VERSION 5.7 ;
  NOWIREEXTENSIONATPIN ON ;
  DIVIDERCHAR "/" ;
  BUSBITCHARS "[]" ;
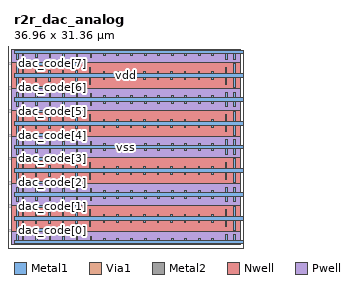
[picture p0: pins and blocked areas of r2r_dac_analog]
MACRO r2r_dac_analog
  CLASS BLOCK ;
  FOREIGN r2r_dac_analog ;
  ORIGIN -165.520 0.000 ;
  SIZE 36.960 BY 31.360 ;
  PIN dac_code[7]
    ANTENNAGATEAREA 11.020000 ;
    PORT
      LAYER Metal1 ;
        RECT 167.270 29.210 176.540 29.620 ;
    END
  END dac_code[7]
  PIN dac_code[6]
    ANTENNAGATEAREA 11.020000 ;
    PORT
      LAYER Metal1 ;
        RECT 167.270 25.260 176.540 25.670 ;
    END
  END dac_code[6]
  PIN dac_code[5]
    ANTENNAGATEAREA 11.020000 ;
    PORT
      LAYER Metal1 ;
        RECT 167.270 21.370 176.540 21.780 ;
    END
  END dac_code[5]
  PIN dac_code[4]
    ANTENNAGATEAREA 11.020000 ;
    PORT
      LAYER Metal1 ;
        RECT 167.270 17.420 176.540 17.830 ;
    END
  END dac_code[4]
  PIN dac_code[3]
    ANTENNAGATEAREA 11.020000 ;
    PORT
      LAYER Metal1 ;
        RECT 167.270 13.530 176.540 13.940 ;
    END
  END dac_code[3]
  PIN dac_code[2]
    ANTENNAGATEAREA 11.020000 ;
    PORT
      LAYER Metal1 ;
        RECT 167.270 9.580 176.540 9.990 ;
    END
  END dac_code[2]
  PIN dac_code[1]
    ANTENNAGATEAREA 11.020000 ;
    PORT
      LAYER Metal1 ;
        RECT 167.270 5.690 176.540 6.100 ;
    END
  END dac_code[1]
  PIN dac_code[0]
    ANTENNAGATEAREA 11.020000 ;
    PORT
      LAYER Metal1 ;
        RECT 167.270 1.740 176.540 2.150 ;
    END
  END dac_code[0]
  PIN vout
    DIRECTION INOUT ;
    USE SIGNAL ;
    PORT
      LAYER Metal1 ;
        RECT -0.520 130.010 -0.140 130.060 ;
        RECT -0.530 129.610 -0.130 130.010 ;
        RECT -0.520 128.660 -0.140 129.610 ;
        RECT -0.520 126.010 -0.140 126.060 ;
        RECT -0.530 125.610 -0.130 126.010 ;
        RECT 153.320 125.610 153.720 130.010 ;
        RECT -0.520 124.660 -0.140 125.610 ;
      LAYER Via1 ;
        RECT -0.460 129.680 -0.200 129.940 ;
        RECT 153.390 129.680 153.650 129.940 ;
        RECT -0.460 125.680 -0.200 125.940 ;
        RECT 153.390 125.680 153.650 125.940 ;
      LAYER Metal2 ;
        RECT -0.530 129.610 153.720 130.010 ;
        RECT -0.530 125.610 153.720 126.010 ;
    END
  END vout
  PIN vdd
    DIRECTION INOUT ;
    USE POWER ;
    PORT
      LAYER Nwell ;
        RECT 165.090 25.280 202.910 29.600 ;
        RECT 165.090 17.440 202.910 21.760 ;
        RECT 165.090 9.600 202.910 13.920 ;
        RECT 165.090 1.760 202.910 6.080 ;
      LAYER Metal1 ;
        RECT 165.910 27.740 166.250 29.430 ;
        RECT 166.885 27.740 167.115 28.830 ;
        RECT 169.025 27.740 169.255 28.360 ;
        RECT 171.265 27.740 171.495 28.360 ;
        RECT 173.505 27.740 173.735 28.360 ;
        RECT 175.745 27.740 175.975 28.360 ;
        RECT 177.985 27.740 178.215 28.830 ;
        RECT 180.225 27.740 180.455 28.130 ;
        RECT 182.465 27.740 182.695 28.130 ;
        RECT 184.705 27.740 184.935 28.130 ;
        RECT 186.945 27.740 187.175 28.130 ;
        RECT 189.185 27.740 189.415 28.130 ;
        RECT 191.425 27.740 191.655 28.130 ;
        RECT 193.665 27.740 193.895 28.130 ;
        RECT 195.905 27.740 196.135 28.130 ;
        RECT 198.145 27.740 198.375 28.130 ;
        RECT 200.385 27.740 200.615 28.830 ;
        RECT 201.750 27.740 202.090 29.430 ;
        RECT 165.520 27.140 204.280 27.740 ;
        RECT 165.910 25.450 166.250 27.140 ;
        RECT 166.885 26.050 167.115 27.140 ;
        RECT 169.025 26.520 169.255 27.140 ;
        RECT 171.265 26.520 171.495 27.140 ;
        RECT 173.505 26.520 173.735 27.140 ;
        RECT 175.745 26.520 175.975 27.140 ;
        RECT 177.985 26.050 178.215 27.140 ;
        RECT 180.225 26.750 180.455 27.140 ;
        RECT 182.465 26.750 182.695 27.140 ;
        RECT 184.705 26.750 184.935 27.140 ;
        RECT 186.945 26.750 187.175 27.140 ;
        RECT 189.185 26.750 189.415 27.140 ;
        RECT 191.425 26.750 191.655 27.140 ;
        RECT 193.665 26.750 193.895 27.140 ;
        RECT 195.905 26.750 196.135 27.140 ;
        RECT 198.145 26.750 198.375 27.140 ;
        RECT 200.385 26.050 200.615 27.140 ;
        RECT 201.750 25.450 202.090 27.140 ;
        RECT 165.910 19.900 166.250 21.590 ;
        RECT 166.885 19.900 167.115 20.990 ;
        RECT 169.025 19.900 169.255 20.520 ;
        RECT 171.265 19.900 171.495 20.520 ;
        RECT 173.505 19.900 173.735 20.520 ;
        RECT 175.745 19.900 175.975 20.520 ;
        RECT 177.985 19.900 178.215 20.990 ;
        RECT 180.225 19.900 180.455 20.290 ;
        RECT 182.465 19.900 182.695 20.290 ;
        RECT 184.705 19.900 184.935 20.290 ;
        RECT 186.945 19.900 187.175 20.290 ;
        RECT 189.185 19.900 189.415 20.290 ;
        RECT 191.425 19.900 191.655 20.290 ;
        RECT 193.665 19.900 193.895 20.290 ;
        RECT 195.905 19.900 196.135 20.290 ;
        RECT 198.145 19.900 198.375 20.290 ;
        RECT 200.385 19.900 200.615 20.990 ;
        RECT 201.750 19.900 202.090 21.590 ;
        RECT 165.520 19.300 204.280 19.900 ;
        RECT 165.910 17.610 166.250 19.300 ;
        RECT 166.885 18.210 167.115 19.300 ;
        RECT 169.025 18.680 169.255 19.300 ;
        RECT 171.265 18.680 171.495 19.300 ;
        RECT 173.505 18.680 173.735 19.300 ;
        RECT 175.745 18.680 175.975 19.300 ;
        RECT 177.985 18.210 178.215 19.300 ;
        RECT 180.225 18.910 180.455 19.300 ;
        RECT 182.465 18.910 182.695 19.300 ;
        RECT 184.705 18.910 184.935 19.300 ;
        RECT 186.945 18.910 187.175 19.300 ;
        RECT 189.185 18.910 189.415 19.300 ;
        RECT 191.425 18.910 191.655 19.300 ;
        RECT 193.665 18.910 193.895 19.300 ;
        RECT 195.905 18.910 196.135 19.300 ;
        RECT 198.145 18.910 198.375 19.300 ;
        RECT 200.385 18.210 200.615 19.300 ;
        RECT 201.750 17.610 202.090 19.300 ;
        RECT 165.910 12.060 166.250 13.750 ;
        RECT 166.885 12.060 167.115 13.150 ;
        RECT 169.025 12.060 169.255 12.680 ;
        RECT 171.265 12.060 171.495 12.680 ;
        RECT 173.505 12.060 173.735 12.680 ;
        RECT 175.745 12.060 175.975 12.680 ;
        RECT 177.985 12.060 178.215 13.150 ;
        RECT 180.225 12.060 180.455 12.450 ;
        RECT 182.465 12.060 182.695 12.450 ;
        RECT 184.705 12.060 184.935 12.450 ;
        RECT 186.945 12.060 187.175 12.450 ;
        RECT 189.185 12.060 189.415 12.450 ;
        RECT 191.425 12.060 191.655 12.450 ;
        RECT 193.665 12.060 193.895 12.450 ;
        RECT 195.905 12.060 196.135 12.450 ;
        RECT 198.145 12.060 198.375 12.450 ;
        RECT 200.385 12.060 200.615 13.150 ;
        RECT 201.750 12.060 202.090 13.750 ;
        RECT 165.520 11.460 204.280 12.060 ;
        RECT 165.910 9.770 166.250 11.460 ;
        RECT 166.885 10.370 167.115 11.460 ;
        RECT 169.025 10.840 169.255 11.460 ;
        RECT 171.265 10.840 171.495 11.460 ;
        RECT 173.505 10.840 173.735 11.460 ;
        RECT 175.745 10.840 175.975 11.460 ;
        RECT 177.985 10.370 178.215 11.460 ;
        RECT 180.225 11.070 180.455 11.460 ;
        RECT 182.465 11.070 182.695 11.460 ;
        RECT 184.705 11.070 184.935 11.460 ;
        RECT 186.945 11.070 187.175 11.460 ;
        RECT 189.185 11.070 189.415 11.460 ;
        RECT 191.425 11.070 191.655 11.460 ;
        RECT 193.665 11.070 193.895 11.460 ;
        RECT 195.905 11.070 196.135 11.460 ;
        RECT 198.145 11.070 198.375 11.460 ;
        RECT 200.385 10.370 200.615 11.460 ;
        RECT 201.750 9.770 202.090 11.460 ;
        RECT 165.910 4.220 166.250 5.910 ;
        RECT 166.885 4.220 167.115 5.310 ;
        RECT 169.025 4.220 169.255 4.840 ;
        RECT 171.265 4.220 171.495 4.840 ;
        RECT 173.505 4.220 173.735 4.840 ;
        RECT 175.745 4.220 175.975 4.840 ;
        RECT 177.985 4.220 178.215 5.310 ;
        RECT 180.225 4.220 180.455 4.610 ;
        RECT 182.465 4.220 182.695 4.610 ;
        RECT 184.705 4.220 184.935 4.610 ;
        RECT 186.945 4.220 187.175 4.610 ;
        RECT 189.185 4.220 189.415 4.610 ;
        RECT 191.425 4.220 191.655 4.610 ;
        RECT 193.665 4.220 193.895 4.610 ;
        RECT 195.905 4.220 196.135 4.610 ;
        RECT 198.145 4.220 198.375 4.610 ;
        RECT 200.385 4.220 200.615 5.310 ;
        RECT 201.750 4.220 202.090 5.910 ;
        RECT 165.520 3.620 204.280 4.220 ;
        RECT 165.910 1.930 166.250 3.620 ;
        RECT 166.885 2.530 167.115 3.620 ;
        RECT 169.025 3.000 169.255 3.620 ;
        RECT 171.265 3.000 171.495 3.620 ;
        RECT 173.505 3.000 173.735 3.620 ;
        RECT 175.745 3.000 175.975 3.620 ;
        RECT 177.985 2.530 178.215 3.620 ;
        RECT 180.225 3.230 180.455 3.620 ;
        RECT 182.465 3.230 182.695 3.620 ;
        RECT 184.705 3.230 184.935 3.620 ;
        RECT 186.945 3.230 187.175 3.620 ;
        RECT 189.185 3.230 189.415 3.620 ;
        RECT 191.425 3.230 191.655 3.620 ;
        RECT 193.665 3.230 193.895 3.620 ;
        RECT 195.905 3.230 196.135 3.620 ;
        RECT 198.145 3.230 198.375 3.620 ;
        RECT 200.385 2.530 200.615 3.620 ;
        RECT 201.750 1.930 202.090 3.620 ;
      LAYER Via1 ;
        RECT 203.850 27.310 204.110 27.570 ;
        RECT 203.850 19.470 204.110 19.730 ;
        RECT 203.850 11.630 204.110 11.890 ;
        RECT 203.850 3.790 204.110 4.050 ;
      LAYER Metal2 ;
        RECT 203.780 3.720 204.180 27.640 ;
    END
  END vdd
  PIN vss
    DIRECTION INOUT ;
    USE GROUND ;
    PORT
      LAYER Pwell ;
        RECT 165.090 29.600 202.910 31.790 ;
        RECT 165.090 21.760 202.910 25.280 ;
        RECT 165.090 13.920 202.910 17.440 ;
        RECT 165.090 6.080 202.910 9.600 ;
        RECT 165.090 -0.430 202.910 1.760 ;
      LAYER Metal1 ;
        RECT -1.890 -2.800 -1.510 136.360 ;
        RECT 150.140 37.110 150.520 38.060 ;
        RECT 150.130 36.710 150.530 37.110 ;
        RECT 150.140 36.660 150.520 36.710 ;
        RECT -1.900 -3.200 -1.500 -2.800 ;
        RECT 152.320 -3.200 152.720 37.110 ;
        RECT 165.520 31.060 205.780 31.660 ;
        RECT 165.910 30.175 166.250 31.060 ;
        RECT 166.885 30.200 167.115 31.060 ;
        RECT 169.125 30.400 169.355 31.060 ;
        RECT 171.365 30.400 171.595 31.060 ;
        RECT 173.605 30.400 173.835 31.060 ;
        RECT 175.845 30.400 176.075 31.060 ;
        RECT 178.085 30.400 178.315 31.060 ;
        RECT 180.270 30.725 180.610 31.060 ;
        RECT 182.510 30.725 182.850 31.060 ;
        RECT 184.750 30.725 185.090 31.060 ;
        RECT 186.990 30.725 187.330 31.060 ;
        RECT 189.230 30.725 189.570 31.060 ;
        RECT 191.470 30.725 191.810 31.060 ;
        RECT 193.710 30.725 194.050 31.060 ;
        RECT 195.950 30.725 196.290 31.060 ;
        RECT 198.190 30.725 198.530 31.060 ;
        RECT 200.485 30.200 200.715 31.060 ;
        RECT 201.750 30.175 202.090 31.060 ;
        RECT 165.910 23.820 166.250 24.705 ;
        RECT 166.885 23.820 167.115 24.680 ;
        RECT 169.125 23.820 169.355 24.480 ;
        RECT 171.365 23.820 171.595 24.480 ;
        RECT 173.605 23.820 173.835 24.480 ;
        RECT 175.845 23.820 176.075 24.480 ;
        RECT 178.085 23.820 178.315 24.480 ;
        RECT 180.270 23.820 180.610 24.155 ;
        RECT 182.510 23.820 182.850 24.155 ;
        RECT 184.750 23.820 185.090 24.155 ;
        RECT 186.990 23.820 187.330 24.155 ;
        RECT 189.230 23.820 189.570 24.155 ;
        RECT 191.470 23.820 191.810 24.155 ;
        RECT 193.710 23.820 194.050 24.155 ;
        RECT 195.950 23.820 196.290 24.155 ;
        RECT 198.190 23.820 198.530 24.155 ;
        RECT 200.485 23.820 200.715 24.680 ;
        RECT 201.750 23.820 202.090 24.705 ;
        RECT 165.520 23.220 205.780 23.820 ;
        RECT 165.910 22.335 166.250 23.220 ;
        RECT 166.885 22.360 167.115 23.220 ;
        RECT 169.125 22.560 169.355 23.220 ;
        RECT 171.365 22.560 171.595 23.220 ;
        RECT 173.605 22.560 173.835 23.220 ;
        RECT 175.845 22.560 176.075 23.220 ;
        RECT 178.085 22.560 178.315 23.220 ;
        RECT 180.270 22.885 180.610 23.220 ;
        RECT 182.510 22.885 182.850 23.220 ;
        RECT 184.750 22.885 185.090 23.220 ;
        RECT 186.990 22.885 187.330 23.220 ;
        RECT 189.230 22.885 189.570 23.220 ;
        RECT 191.470 22.885 191.810 23.220 ;
        RECT 193.710 22.885 194.050 23.220 ;
        RECT 195.950 22.885 196.290 23.220 ;
        RECT 198.190 22.885 198.530 23.220 ;
        RECT 200.485 22.360 200.715 23.220 ;
        RECT 201.750 22.335 202.090 23.220 ;
        RECT 165.910 15.980 166.250 16.865 ;
        RECT 166.885 15.980 167.115 16.840 ;
        RECT 169.125 15.980 169.355 16.640 ;
        RECT 171.365 15.980 171.595 16.640 ;
        RECT 173.605 15.980 173.835 16.640 ;
        RECT 175.845 15.980 176.075 16.640 ;
        RECT 178.085 15.980 178.315 16.640 ;
        RECT 180.270 15.980 180.610 16.315 ;
        RECT 182.510 15.980 182.850 16.315 ;
        RECT 184.750 15.980 185.090 16.315 ;
        RECT 186.990 15.980 187.330 16.315 ;
        RECT 189.230 15.980 189.570 16.315 ;
        RECT 191.470 15.980 191.810 16.315 ;
        RECT 193.710 15.980 194.050 16.315 ;
        RECT 195.950 15.980 196.290 16.315 ;
        RECT 198.190 15.980 198.530 16.315 ;
        RECT 200.485 15.980 200.715 16.840 ;
        RECT 201.750 15.980 202.090 16.865 ;
        RECT 165.520 15.380 205.780 15.980 ;
        RECT 165.910 14.495 166.250 15.380 ;
        RECT 166.885 14.520 167.115 15.380 ;
        RECT 169.125 14.720 169.355 15.380 ;
        RECT 171.365 14.720 171.595 15.380 ;
        RECT 173.605 14.720 173.835 15.380 ;
        RECT 175.845 14.720 176.075 15.380 ;
        RECT 178.085 14.720 178.315 15.380 ;
        RECT 180.270 15.045 180.610 15.380 ;
        RECT 182.510 15.045 182.850 15.380 ;
        RECT 184.750 15.045 185.090 15.380 ;
        RECT 186.990 15.045 187.330 15.380 ;
        RECT 189.230 15.045 189.570 15.380 ;
        RECT 191.470 15.045 191.810 15.380 ;
        RECT 193.710 15.045 194.050 15.380 ;
        RECT 195.950 15.045 196.290 15.380 ;
        RECT 198.190 15.045 198.530 15.380 ;
        RECT 200.485 14.520 200.715 15.380 ;
        RECT 201.750 14.495 202.090 15.380 ;
        RECT 165.910 8.140 166.250 9.025 ;
        RECT 166.885 8.140 167.115 9.000 ;
        RECT 169.125 8.140 169.355 8.800 ;
        RECT 171.365 8.140 171.595 8.800 ;
        RECT 173.605 8.140 173.835 8.800 ;
        RECT 175.845 8.140 176.075 8.800 ;
        RECT 178.085 8.140 178.315 8.800 ;
        RECT 180.270 8.140 180.610 8.475 ;
        RECT 182.510 8.140 182.850 8.475 ;
        RECT 184.750 8.140 185.090 8.475 ;
        RECT 186.990 8.140 187.330 8.475 ;
        RECT 189.230 8.140 189.570 8.475 ;
        RECT 191.470 8.140 191.810 8.475 ;
        RECT 193.710 8.140 194.050 8.475 ;
        RECT 195.950 8.140 196.290 8.475 ;
        RECT 198.190 8.140 198.530 8.475 ;
        RECT 200.485 8.140 200.715 9.000 ;
        RECT 201.750 8.140 202.090 9.025 ;
        RECT 165.520 7.540 205.780 8.140 ;
        RECT 165.910 6.655 166.250 7.540 ;
        RECT 166.885 6.680 167.115 7.540 ;
        RECT 169.125 6.880 169.355 7.540 ;
        RECT 171.365 6.880 171.595 7.540 ;
        RECT 173.605 6.880 173.835 7.540 ;
        RECT 175.845 6.880 176.075 7.540 ;
        RECT 178.085 6.880 178.315 7.540 ;
        RECT 180.270 7.205 180.610 7.540 ;
        RECT 182.510 7.205 182.850 7.540 ;
        RECT 184.750 7.205 185.090 7.540 ;
        RECT 186.990 7.205 187.330 7.540 ;
        RECT 189.230 7.205 189.570 7.540 ;
        RECT 191.470 7.205 191.810 7.540 ;
        RECT 193.710 7.205 194.050 7.540 ;
        RECT 195.950 7.205 196.290 7.540 ;
        RECT 198.190 7.205 198.530 7.540 ;
        RECT 200.485 6.680 200.715 7.540 ;
        RECT 201.750 6.655 202.090 7.540 ;
        RECT 165.910 0.300 166.250 1.185 ;
        RECT 166.885 0.300 167.115 1.160 ;
        RECT 169.125 0.300 169.355 0.960 ;
        RECT 171.365 0.300 171.595 0.960 ;
        RECT 173.605 0.300 173.835 0.960 ;
        RECT 175.845 0.300 176.075 0.960 ;
        RECT 178.085 0.300 178.315 0.960 ;
        RECT 180.270 0.300 180.610 0.635 ;
        RECT 182.510 0.300 182.850 0.635 ;
        RECT 184.750 0.300 185.090 0.635 ;
        RECT 186.990 0.300 187.330 0.635 ;
        RECT 189.230 0.300 189.570 0.635 ;
        RECT 191.470 0.300 191.810 0.635 ;
        RECT 193.710 0.300 194.050 0.635 ;
        RECT 195.950 0.300 196.290 0.635 ;
        RECT 198.190 0.300 198.530 0.635 ;
        RECT 200.485 0.300 200.715 1.160 ;
        RECT 201.750 0.300 202.090 1.185 ;
        RECT 165.520 -0.300 205.780 0.300 ;
        RECT 205.280 -3.200 205.680 -2.800 ;
      LAYER Via1 ;
        RECT 150.200 36.780 150.460 37.040 ;
        RECT 152.390 36.780 152.650 37.040 ;
        RECT -1.830 -3.130 -1.570 -2.870 ;
        RECT 205.350 31.230 205.610 31.490 ;
        RECT 205.350 23.390 205.610 23.650 ;
        RECT 205.350 15.550 205.610 15.810 ;
        RECT 205.350 7.710 205.610 7.970 ;
        RECT 205.350 -0.130 205.610 0.130 ;
        RECT 152.390 -3.130 152.650 -2.870 ;
        RECT 205.350 -3.130 205.610 -2.870 ;
      LAYER Metal2 ;
        RECT 150.130 36.710 152.720 37.110 ;
        RECT 205.280 -2.800 205.680 31.560 ;
        RECT -1.900 -3.200 205.680 -2.800 ;
    END
  END vss
  OBS
      LAYER Metal1 ;
        RECT -0.520 134.010 -0.140 134.060 ;
        RECT -0.530 133.610 -0.130 134.010 ;
        RECT -0.520 132.660 -0.140 133.610 ;
        RECT 150.140 133.110 150.520 134.060 ;
        RECT 150.130 132.710 150.530 133.110 ;
        RECT 150.140 132.660 150.520 132.710 ;
        RECT 148.500 129.110 148.880 130.060 ;
        RECT 148.490 128.710 148.890 129.110 ;
        RECT 152.320 128.710 152.720 133.110 ;
        RECT 148.500 128.660 148.880 128.710 ;
        RECT 150.140 125.110 150.520 126.060 ;
        RECT 150.130 124.710 150.530 125.110 ;
        RECT 150.140 124.660 150.520 124.710 ;
        RECT -0.520 122.010 -0.140 122.060 ;
        RECT -0.530 121.610 -0.130 122.010 ;
        RECT -0.520 120.660 -0.140 121.610 ;
        RECT 150.140 121.110 150.520 122.060 ;
        RECT 150.130 120.710 150.530 121.110 ;
        RECT 150.140 120.660 150.520 120.710 ;
        RECT -0.520 118.010 -0.140 118.060 ;
        RECT -0.530 117.610 -0.130 118.010 ;
        RECT -0.520 116.660 -0.140 117.610 ;
        RECT 148.500 117.110 148.880 118.060 ;
        RECT 148.490 116.710 148.890 117.110 ;
        RECT 148.500 116.660 148.880 116.710 ;
        RECT -0.520 114.010 -0.140 114.060 ;
        RECT -0.530 113.610 -0.130 114.010 ;
        RECT -0.520 112.660 -0.140 113.610 ;
        RECT 150.140 113.110 150.520 114.060 ;
        RECT 152.320 113.610 152.720 125.110 ;
        RECT 153.320 116.710 153.720 121.110 ;
        RECT 150.130 112.710 150.530 113.110 ;
        RECT 150.140 112.660 150.520 112.710 ;
        RECT -0.520 110.010 -0.140 110.060 ;
        RECT -0.530 109.610 -0.130 110.010 ;
        RECT -0.520 108.660 -0.140 109.610 ;
        RECT 150.140 109.110 150.520 110.060 ;
        RECT 150.130 108.710 150.530 109.110 ;
        RECT 150.140 108.660 150.520 108.710 ;
        RECT -0.520 106.010 -0.140 106.060 ;
        RECT -0.530 105.610 -0.130 106.010 ;
        RECT -0.520 104.660 -0.140 105.610 ;
        RECT 148.500 105.110 148.880 106.060 ;
        RECT 148.490 104.710 148.890 105.110 ;
        RECT 152.320 104.710 152.720 109.110 ;
        RECT 148.500 104.660 148.880 104.710 ;
        RECT -0.520 102.010 -0.140 102.060 ;
        RECT -0.530 101.610 -0.130 102.010 ;
        RECT -0.520 100.660 -0.140 101.610 ;
        RECT 150.140 101.110 150.520 102.060 ;
        RECT 153.320 101.610 153.720 113.110 ;
        RECT 150.130 100.710 150.530 101.110 ;
        RECT 150.140 100.660 150.520 100.710 ;
        RECT -0.520 98.010 -0.140 98.060 ;
        RECT -0.530 97.610 -0.130 98.010 ;
        RECT -0.520 96.660 -0.140 97.610 ;
        RECT 150.140 97.110 150.520 98.060 ;
        RECT 150.130 96.710 150.530 97.110 ;
        RECT 150.140 96.660 150.520 96.710 ;
        RECT -0.520 94.010 -0.140 94.060 ;
        RECT -0.530 93.610 -0.130 94.010 ;
        RECT -0.520 92.660 -0.140 93.610 ;
        RECT 148.500 93.110 148.880 94.060 ;
        RECT 148.490 92.710 148.890 93.110 ;
        RECT 148.500 92.660 148.880 92.710 ;
        RECT -0.520 90.010 -0.140 90.060 ;
        RECT -0.530 89.610 -0.130 90.010 ;
        RECT -0.520 88.660 -0.140 89.610 ;
        RECT 150.140 89.110 150.520 90.060 ;
        RECT 152.320 89.610 152.720 101.110 ;
        RECT 153.320 92.710 153.720 97.110 ;
        RECT 150.130 88.710 150.530 89.110 ;
        RECT 150.140 88.660 150.520 88.710 ;
        RECT -0.520 86.010 -0.140 86.060 ;
        RECT -0.530 85.610 -0.130 86.010 ;
        RECT -0.520 84.660 -0.140 85.610 ;
        RECT 150.140 85.110 150.520 86.060 ;
        RECT 150.130 84.710 150.530 85.110 ;
        RECT 150.140 84.660 150.520 84.710 ;
        RECT -0.520 82.010 -0.140 82.060 ;
        RECT -0.530 81.610 -0.130 82.010 ;
        RECT -0.520 80.660 -0.140 81.610 ;
        RECT 148.500 81.110 148.880 82.060 ;
        RECT 148.490 80.710 148.890 81.110 ;
        RECT 152.320 80.710 152.720 85.110 ;
        RECT 148.500 80.660 148.880 80.710 ;
        RECT -0.520 78.010 -0.140 78.060 ;
        RECT -0.530 77.610 -0.130 78.010 ;
        RECT -0.520 76.660 -0.140 77.610 ;
        RECT 150.140 77.110 150.520 78.060 ;
        RECT 153.320 77.610 153.720 89.110 ;
        RECT 150.130 76.710 150.530 77.110 ;
        RECT 150.140 76.660 150.520 76.710 ;
        RECT -0.520 74.010 -0.140 74.060 ;
        RECT -0.530 73.610 -0.130 74.010 ;
        RECT -0.520 72.660 -0.140 73.610 ;
        RECT 150.140 73.110 150.520 74.060 ;
        RECT 150.130 72.710 150.530 73.110 ;
        RECT 150.140 72.660 150.520 72.710 ;
        RECT -0.520 70.010 -0.140 70.060 ;
        RECT -0.530 69.610 -0.130 70.010 ;
        RECT -0.520 68.660 -0.140 69.610 ;
        RECT 148.500 69.110 148.880 70.060 ;
        RECT 148.490 68.710 148.890 69.110 ;
        RECT 148.500 68.660 148.880 68.710 ;
        RECT -0.520 66.010 -0.140 66.060 ;
        RECT -0.530 65.610 -0.130 66.010 ;
        RECT -0.520 64.660 -0.140 65.610 ;
        RECT 150.140 65.110 150.520 66.060 ;
        RECT 152.320 65.610 152.720 77.110 ;
        RECT 153.320 68.710 153.720 73.110 ;
        RECT 150.130 64.710 150.530 65.110 ;
        RECT 150.140 64.660 150.520 64.710 ;
        RECT -0.520 62.010 -0.140 62.060 ;
        RECT -0.530 61.610 -0.130 62.010 ;
        RECT -0.520 60.660 -0.140 61.610 ;
        RECT 150.140 61.110 150.520 62.060 ;
        RECT 150.130 60.710 150.530 61.110 ;
        RECT 150.140 60.660 150.520 60.710 ;
        RECT -0.520 58.010 -0.140 58.060 ;
        RECT -0.530 57.610 -0.130 58.010 ;
        RECT -0.520 56.660 -0.140 57.610 ;
        RECT 148.500 57.110 148.880 58.060 ;
        RECT 148.490 56.710 148.890 57.110 ;
        RECT 152.320 56.710 152.720 61.110 ;
        RECT 148.500 56.660 148.880 56.710 ;
        RECT -0.520 54.010 -0.140 54.060 ;
        RECT -0.530 53.610 -0.130 54.010 ;
        RECT -0.520 52.660 -0.140 53.610 ;
        RECT 150.140 53.110 150.520 54.060 ;
        RECT 153.320 53.610 153.720 65.110 ;
        RECT 150.130 52.710 150.530 53.110 ;
        RECT 150.140 52.660 150.520 52.710 ;
        RECT -0.520 50.010 -0.140 50.060 ;
        RECT -0.530 49.610 -0.130 50.010 ;
        RECT -0.520 48.660 -0.140 49.610 ;
        RECT 150.140 49.110 150.520 50.060 ;
        RECT 150.130 48.710 150.530 49.110 ;
        RECT 150.140 48.660 150.520 48.710 ;
        RECT -0.520 46.010 -0.140 46.060 ;
        RECT -0.530 45.610 -0.130 46.010 ;
        RECT -0.520 44.660 -0.140 45.610 ;
        RECT 148.500 45.110 148.880 46.060 ;
        RECT 148.490 44.710 148.890 45.110 ;
        RECT 148.500 44.660 148.880 44.710 ;
        RECT -0.520 42.010 -0.140 42.060 ;
        RECT -0.530 41.610 -0.130 42.010 ;
        RECT -0.520 40.660 -0.140 41.610 ;
        RECT 150.140 41.110 150.520 42.060 ;
        RECT 152.320 41.610 152.720 53.110 ;
        RECT 150.130 40.710 150.530 41.110 ;
        RECT 150.140 40.660 150.520 40.710 ;
        RECT -0.520 38.010 -0.140 38.060 ;
        RECT -0.530 37.610 -0.130 38.010 ;
        RECT -0.520 36.660 -0.140 37.610 ;
        RECT 153.320 1.690 153.720 50.010 ;
        RECT 154.320 5.750 154.720 62.010 ;
        RECT 155.320 9.530 155.720 74.010 ;
        RECT 156.320 13.590 156.720 86.010 ;
        RECT 157.320 17.370 157.720 98.010 ;
        RECT 158.320 21.430 158.720 110.010 ;
        RECT 159.320 25.210 159.720 122.010 ;
        RECT 160.320 29.270 160.720 134.010 ;
        RECT 161.320 44.710 161.720 49.110 ;
        RECT 161.320 37.610 161.720 41.110 ;
        RECT 168.005 30.170 168.235 30.685 ;
        RECT 170.245 30.170 170.475 30.685 ;
        RECT 172.485 30.170 172.715 30.685 ;
        RECT 174.725 30.170 174.955 30.685 ;
        RECT 176.965 30.170 177.320 30.685 ;
        RECT 168.005 29.940 177.320 30.170 ;
        RECT 176.865 29.620 177.320 29.940 ;
        RECT 179.205 30.495 179.465 30.685 ;
        RECT 181.445 30.495 181.675 30.685 ;
        RECT 183.685 30.495 183.915 30.685 ;
        RECT 185.925 30.495 186.155 30.685 ;
        RECT 188.165 30.495 188.395 30.685 ;
        RECT 190.405 30.495 190.635 30.685 ;
        RECT 192.645 30.495 192.875 30.685 ;
        RECT 194.885 30.495 195.115 30.685 ;
        RECT 197.125 30.495 197.355 30.685 ;
        RECT 199.365 30.495 199.595 30.685 ;
        RECT 179.205 29.850 199.595 30.495 ;
        RECT 176.865 29.390 188.210 29.620 ;
        RECT 176.865 28.830 177.320 29.390 ;
        RECT 188.870 29.090 189.770 29.850 ;
        RECT 190.320 29.390 200.240 29.620 ;
        RECT 168.005 28.600 177.320 28.830 ;
        RECT 168.005 27.980 168.235 28.600 ;
        RECT 170.145 27.980 170.375 28.600 ;
        RECT 172.385 27.980 172.615 28.600 ;
        RECT 174.625 27.980 174.855 28.600 ;
        RECT 176.865 27.980 177.320 28.600 ;
        RECT 179.205 28.360 199.495 29.090 ;
        RECT 179.205 27.980 179.435 28.360 ;
        RECT 181.345 27.980 181.575 28.360 ;
        RECT 183.585 27.980 183.815 28.360 ;
        RECT 185.825 27.980 186.055 28.360 ;
        RECT 188.065 27.980 188.295 28.360 ;
        RECT 190.305 27.980 190.535 28.360 ;
        RECT 192.545 27.980 192.775 28.360 ;
        RECT 194.785 27.980 195.015 28.360 ;
        RECT 197.025 27.980 197.255 28.360 ;
        RECT 199.265 27.980 199.495 28.360 ;
        RECT 168.005 26.280 168.235 26.900 ;
        RECT 170.145 26.280 170.375 26.900 ;
        RECT 172.385 26.280 172.615 26.900 ;
        RECT 174.625 26.280 174.855 26.900 ;
        RECT 176.865 26.280 177.320 26.900 ;
        RECT 168.005 26.050 177.320 26.280 ;
        RECT 176.865 25.490 177.320 26.050 ;
        RECT 179.205 26.520 179.435 26.900 ;
        RECT 181.345 26.520 181.575 26.900 ;
        RECT 183.585 26.520 183.815 26.900 ;
        RECT 185.825 26.520 186.055 26.900 ;
        RECT 188.065 26.520 188.295 26.900 ;
        RECT 190.305 26.520 190.535 26.900 ;
        RECT 192.545 26.520 192.775 26.900 ;
        RECT 194.785 26.520 195.015 26.900 ;
        RECT 197.025 26.520 197.255 26.900 ;
        RECT 199.265 26.520 199.495 26.900 ;
        RECT 179.205 25.790 199.495 26.520 ;
        RECT 176.865 25.260 188.210 25.490 ;
        RECT 176.865 24.940 177.320 25.260 ;
        RECT 188.870 25.030 189.770 25.790 ;
        RECT 190.320 25.260 200.240 25.490 ;
        RECT 168.005 24.710 177.320 24.940 ;
        RECT 168.005 24.195 168.235 24.710 ;
        RECT 170.245 24.195 170.475 24.710 ;
        RECT 172.485 24.195 172.715 24.710 ;
        RECT 174.725 24.195 174.955 24.710 ;
        RECT 176.965 24.195 177.320 24.710 ;
        RECT 179.205 24.385 199.595 25.030 ;
        RECT 179.205 24.195 179.465 24.385 ;
        RECT 181.445 24.195 181.675 24.385 ;
        RECT 183.685 24.195 183.915 24.385 ;
        RECT 185.925 24.195 186.155 24.385 ;
        RECT 188.165 24.195 188.395 24.385 ;
        RECT 190.405 24.195 190.635 24.385 ;
        RECT 192.645 24.195 192.875 24.385 ;
        RECT 194.885 24.195 195.115 24.385 ;
        RECT 197.125 24.195 197.355 24.385 ;
        RECT 199.365 24.195 199.595 24.385 ;
        RECT 168.005 22.330 168.235 22.845 ;
        RECT 170.245 22.330 170.475 22.845 ;
        RECT 172.485 22.330 172.715 22.845 ;
        RECT 174.725 22.330 174.955 22.845 ;
        RECT 176.965 22.330 177.320 22.845 ;
        RECT 168.005 22.100 177.320 22.330 ;
        RECT 176.865 21.780 177.320 22.100 ;
        RECT 179.205 22.655 179.465 22.845 ;
        RECT 181.445 22.655 181.675 22.845 ;
        RECT 183.685 22.655 183.915 22.845 ;
        RECT 185.925 22.655 186.155 22.845 ;
        RECT 188.165 22.655 188.395 22.845 ;
        RECT 190.405 22.655 190.635 22.845 ;
        RECT 192.645 22.655 192.875 22.845 ;
        RECT 194.885 22.655 195.115 22.845 ;
        RECT 197.125 22.655 197.355 22.845 ;
        RECT 199.365 22.655 199.595 22.845 ;
        RECT 179.205 22.010 199.595 22.655 ;
        RECT 176.865 21.550 188.210 21.780 ;
        RECT 176.865 20.990 177.320 21.550 ;
        RECT 188.870 21.250 189.770 22.010 ;
        RECT 190.320 21.550 200.240 21.780 ;
        RECT 168.005 20.760 177.320 20.990 ;
        RECT 168.005 20.140 168.235 20.760 ;
        RECT 170.145 20.140 170.375 20.760 ;
        RECT 172.385 20.140 172.615 20.760 ;
        RECT 174.625 20.140 174.855 20.760 ;
        RECT 176.865 20.140 177.320 20.760 ;
        RECT 179.205 20.520 199.495 21.250 ;
        RECT 179.205 20.140 179.435 20.520 ;
        RECT 181.345 20.140 181.575 20.520 ;
        RECT 183.585 20.140 183.815 20.520 ;
        RECT 185.825 20.140 186.055 20.520 ;
        RECT 188.065 20.140 188.295 20.520 ;
        RECT 190.305 20.140 190.535 20.520 ;
        RECT 192.545 20.140 192.775 20.520 ;
        RECT 194.785 20.140 195.015 20.520 ;
        RECT 197.025 20.140 197.255 20.520 ;
        RECT 199.265 20.140 199.495 20.520 ;
        RECT 168.005 18.440 168.235 19.060 ;
        RECT 170.145 18.440 170.375 19.060 ;
        RECT 172.385 18.440 172.615 19.060 ;
        RECT 174.625 18.440 174.855 19.060 ;
        RECT 176.865 18.440 177.320 19.060 ;
        RECT 168.005 18.210 177.320 18.440 ;
        RECT 176.865 17.650 177.320 18.210 ;
        RECT 179.205 18.680 179.435 19.060 ;
        RECT 181.345 18.680 181.575 19.060 ;
        RECT 183.585 18.680 183.815 19.060 ;
        RECT 185.825 18.680 186.055 19.060 ;
        RECT 188.065 18.680 188.295 19.060 ;
        RECT 190.305 18.680 190.535 19.060 ;
        RECT 192.545 18.680 192.775 19.060 ;
        RECT 194.785 18.680 195.015 19.060 ;
        RECT 197.025 18.680 197.255 19.060 ;
        RECT 199.265 18.680 199.495 19.060 ;
        RECT 179.205 17.950 199.495 18.680 ;
        RECT 176.865 17.420 188.210 17.650 ;
        RECT 176.865 17.100 177.320 17.420 ;
        RECT 188.870 17.190 189.770 17.950 ;
        RECT 190.320 17.420 200.240 17.650 ;
        RECT 168.005 16.870 177.320 17.100 ;
        RECT 168.005 16.355 168.235 16.870 ;
        RECT 170.245 16.355 170.475 16.870 ;
        RECT 172.485 16.355 172.715 16.870 ;
        RECT 174.725 16.355 174.955 16.870 ;
        RECT 176.965 16.355 177.320 16.870 ;
        RECT 179.205 16.545 199.595 17.190 ;
        RECT 179.205 16.355 179.465 16.545 ;
        RECT 181.445 16.355 181.675 16.545 ;
        RECT 183.685 16.355 183.915 16.545 ;
        RECT 185.925 16.355 186.155 16.545 ;
        RECT 188.165 16.355 188.395 16.545 ;
        RECT 190.405 16.355 190.635 16.545 ;
        RECT 192.645 16.355 192.875 16.545 ;
        RECT 194.885 16.355 195.115 16.545 ;
        RECT 197.125 16.355 197.355 16.545 ;
        RECT 199.365 16.355 199.595 16.545 ;
        RECT 168.005 14.490 168.235 15.005 ;
        RECT 170.245 14.490 170.475 15.005 ;
        RECT 172.485 14.490 172.715 15.005 ;
        RECT 174.725 14.490 174.955 15.005 ;
        RECT 176.965 14.490 177.320 15.005 ;
        RECT 168.005 14.260 177.320 14.490 ;
        RECT 176.865 13.940 177.320 14.260 ;
        RECT 179.205 14.815 179.465 15.005 ;
        RECT 181.445 14.815 181.675 15.005 ;
        RECT 183.685 14.815 183.915 15.005 ;
        RECT 185.925 14.815 186.155 15.005 ;
        RECT 188.165 14.815 188.395 15.005 ;
        RECT 190.405 14.815 190.635 15.005 ;
        RECT 192.645 14.815 192.875 15.005 ;
        RECT 194.885 14.815 195.115 15.005 ;
        RECT 197.125 14.815 197.355 15.005 ;
        RECT 199.365 14.815 199.595 15.005 ;
        RECT 179.205 14.170 199.595 14.815 ;
        RECT 176.865 13.710 188.210 13.940 ;
        RECT 176.865 13.150 177.320 13.710 ;
        RECT 188.870 13.410 189.770 14.170 ;
        RECT 190.320 13.710 200.240 13.940 ;
        RECT 168.005 12.920 177.320 13.150 ;
        RECT 168.005 12.300 168.235 12.920 ;
        RECT 170.145 12.300 170.375 12.920 ;
        RECT 172.385 12.300 172.615 12.920 ;
        RECT 174.625 12.300 174.855 12.920 ;
        RECT 176.865 12.300 177.320 12.920 ;
        RECT 179.205 12.680 199.495 13.410 ;
        RECT 179.205 12.300 179.435 12.680 ;
        RECT 181.345 12.300 181.575 12.680 ;
        RECT 183.585 12.300 183.815 12.680 ;
        RECT 185.825 12.300 186.055 12.680 ;
        RECT 188.065 12.300 188.295 12.680 ;
        RECT 190.305 12.300 190.535 12.680 ;
        RECT 192.545 12.300 192.775 12.680 ;
        RECT 194.785 12.300 195.015 12.680 ;
        RECT 197.025 12.300 197.255 12.680 ;
        RECT 199.265 12.300 199.495 12.680 ;
        RECT 168.005 10.600 168.235 11.220 ;
        RECT 170.145 10.600 170.375 11.220 ;
        RECT 172.385 10.600 172.615 11.220 ;
        RECT 174.625 10.600 174.855 11.220 ;
        RECT 176.865 10.600 177.320 11.220 ;
        RECT 168.005 10.370 177.320 10.600 ;
        RECT 176.865 9.810 177.320 10.370 ;
        RECT 179.205 10.840 179.435 11.220 ;
        RECT 181.345 10.840 181.575 11.220 ;
        RECT 183.585 10.840 183.815 11.220 ;
        RECT 185.825 10.840 186.055 11.220 ;
        RECT 188.065 10.840 188.295 11.220 ;
        RECT 190.305 10.840 190.535 11.220 ;
        RECT 192.545 10.840 192.775 11.220 ;
        RECT 194.785 10.840 195.015 11.220 ;
        RECT 197.025 10.840 197.255 11.220 ;
        RECT 199.265 10.840 199.495 11.220 ;
        RECT 179.205 10.110 199.495 10.840 ;
        RECT 176.865 9.580 188.210 9.810 ;
        RECT 176.865 9.260 177.320 9.580 ;
        RECT 188.870 9.350 189.770 10.110 ;
        RECT 190.320 9.580 200.240 9.810 ;
        RECT 168.005 9.030 177.320 9.260 ;
        RECT 168.005 8.515 168.235 9.030 ;
        RECT 170.245 8.515 170.475 9.030 ;
        RECT 172.485 8.515 172.715 9.030 ;
        RECT 174.725 8.515 174.955 9.030 ;
        RECT 176.965 8.515 177.320 9.030 ;
        RECT 179.205 8.705 199.595 9.350 ;
        RECT 179.205 8.515 179.465 8.705 ;
        RECT 181.445 8.515 181.675 8.705 ;
        RECT 183.685 8.515 183.915 8.705 ;
        RECT 185.925 8.515 186.155 8.705 ;
        RECT 188.165 8.515 188.395 8.705 ;
        RECT 190.405 8.515 190.635 8.705 ;
        RECT 192.645 8.515 192.875 8.705 ;
        RECT 194.885 8.515 195.115 8.705 ;
        RECT 197.125 8.515 197.355 8.705 ;
        RECT 199.365 8.515 199.595 8.705 ;
        RECT 168.005 6.650 168.235 7.165 ;
        RECT 170.245 6.650 170.475 7.165 ;
        RECT 172.485 6.650 172.715 7.165 ;
        RECT 174.725 6.650 174.955 7.165 ;
        RECT 176.965 6.650 177.320 7.165 ;
        RECT 168.005 6.420 177.320 6.650 ;
        RECT 176.865 6.100 177.320 6.420 ;
        RECT 179.205 6.975 179.465 7.165 ;
        RECT 181.445 6.975 181.675 7.165 ;
        RECT 183.685 6.975 183.915 7.165 ;
        RECT 185.925 6.975 186.155 7.165 ;
        RECT 188.165 6.975 188.395 7.165 ;
        RECT 190.405 6.975 190.635 7.165 ;
        RECT 192.645 6.975 192.875 7.165 ;
        RECT 194.885 6.975 195.115 7.165 ;
        RECT 197.125 6.975 197.355 7.165 ;
        RECT 199.365 6.975 199.595 7.165 ;
        RECT 179.205 6.330 199.595 6.975 ;
        RECT 176.865 5.870 188.210 6.100 ;
        RECT 176.865 5.310 177.320 5.870 ;
        RECT 188.870 5.570 189.770 6.330 ;
        RECT 190.320 5.870 200.240 6.100 ;
        RECT 168.005 5.080 177.320 5.310 ;
        RECT 168.005 4.460 168.235 5.080 ;
        RECT 170.145 4.460 170.375 5.080 ;
        RECT 172.385 4.460 172.615 5.080 ;
        RECT 174.625 4.460 174.855 5.080 ;
        RECT 176.865 4.460 177.320 5.080 ;
        RECT 179.205 4.840 199.495 5.570 ;
        RECT 179.205 4.460 179.435 4.840 ;
        RECT 181.345 4.460 181.575 4.840 ;
        RECT 183.585 4.460 183.815 4.840 ;
        RECT 185.825 4.460 186.055 4.840 ;
        RECT 188.065 4.460 188.295 4.840 ;
        RECT 190.305 4.460 190.535 4.840 ;
        RECT 192.545 4.460 192.775 4.840 ;
        RECT 194.785 4.460 195.015 4.840 ;
        RECT 197.025 4.460 197.255 4.840 ;
        RECT 199.265 4.460 199.495 4.840 ;
        RECT 168.005 2.760 168.235 3.380 ;
        RECT 170.145 2.760 170.375 3.380 ;
        RECT 172.385 2.760 172.615 3.380 ;
        RECT 174.625 2.760 174.855 3.380 ;
        RECT 176.865 2.760 177.320 3.380 ;
        RECT 168.005 2.530 177.320 2.760 ;
        RECT 176.865 1.970 177.320 2.530 ;
        RECT 179.205 3.000 179.435 3.380 ;
        RECT 181.345 3.000 181.575 3.380 ;
        RECT 183.585 3.000 183.815 3.380 ;
        RECT 185.825 3.000 186.055 3.380 ;
        RECT 188.065 3.000 188.295 3.380 ;
        RECT 190.305 3.000 190.535 3.380 ;
        RECT 192.545 3.000 192.775 3.380 ;
        RECT 194.785 3.000 195.015 3.380 ;
        RECT 197.025 3.000 197.255 3.380 ;
        RECT 199.265 3.000 199.495 3.380 ;
        RECT 179.205 2.270 199.495 3.000 ;
        RECT 176.865 1.740 188.210 1.970 ;
        RECT 176.865 1.420 177.320 1.740 ;
        RECT 188.870 1.510 189.770 2.270 ;
        RECT 190.320 1.740 200.240 1.970 ;
        RECT 168.005 1.190 177.320 1.420 ;
        RECT 168.005 0.675 168.235 1.190 ;
        RECT 170.245 0.675 170.475 1.190 ;
        RECT 172.485 0.675 172.715 1.190 ;
        RECT 174.725 0.675 174.955 1.190 ;
        RECT 176.965 0.675 177.320 1.190 ;
        RECT 179.205 0.865 199.595 1.510 ;
        RECT 179.205 0.675 179.465 0.865 ;
        RECT 181.445 0.675 181.675 0.865 ;
        RECT 183.685 0.675 183.915 0.865 ;
        RECT 185.925 0.675 186.155 0.865 ;
        RECT 188.165 0.675 188.395 0.865 ;
        RECT 190.405 0.675 190.635 0.865 ;
        RECT 192.645 0.675 192.875 0.865 ;
        RECT 194.885 0.675 195.115 0.865 ;
        RECT 197.125 0.675 197.355 0.865 ;
        RECT 199.365 0.675 199.595 0.865 ;
      LAYER Via1 ;
        RECT -0.460 133.680 -0.200 133.940 ;
        RECT 160.390 133.680 160.650 133.940 ;
        RECT 150.200 132.780 150.460 133.040 ;
        RECT 152.390 132.780 152.650 133.040 ;
        RECT 148.560 128.780 148.820 129.040 ;
        RECT 152.390 128.780 152.650 129.040 ;
        RECT 150.200 124.780 150.460 125.040 ;
        RECT 152.390 124.780 152.650 125.040 ;
        RECT -0.460 121.680 -0.200 121.940 ;
        RECT 150.200 120.780 150.460 121.040 ;
        RECT -0.460 117.680 -0.200 117.940 ;
        RECT 159.390 121.680 159.650 121.940 ;
        RECT 152.390 117.680 152.650 117.940 ;
        RECT 148.560 116.780 148.820 117.040 ;
        RECT -0.460 113.680 -0.200 113.940 ;
        RECT 153.390 120.780 153.650 121.040 ;
        RECT 153.390 116.780 153.650 117.040 ;
        RECT 152.390 113.680 152.650 113.940 ;
        RECT 150.200 112.780 150.460 113.040 ;
        RECT 153.390 112.780 153.650 113.040 ;
        RECT -0.460 109.680 -0.200 109.940 ;
        RECT 150.200 108.780 150.460 109.040 ;
        RECT 152.390 108.780 152.650 109.040 ;
        RECT -0.460 105.680 -0.200 105.940 ;
        RECT 148.560 104.780 148.820 105.040 ;
        RECT 152.390 104.780 152.650 105.040 ;
        RECT 153.390 105.680 153.650 105.940 ;
        RECT -0.460 101.680 -0.200 101.940 ;
        RECT 153.390 101.680 153.650 101.940 ;
        RECT 158.390 109.680 158.650 109.940 ;
        RECT 150.200 100.780 150.460 101.040 ;
        RECT 152.390 100.780 152.650 101.040 ;
        RECT -0.460 97.680 -0.200 97.940 ;
        RECT 150.200 96.780 150.460 97.040 ;
        RECT -0.460 93.680 -0.200 93.940 ;
        RECT 157.390 97.680 157.650 97.940 ;
        RECT 152.390 93.680 152.650 93.940 ;
        RECT 148.560 92.780 148.820 93.040 ;
        RECT -0.460 89.680 -0.200 89.940 ;
        RECT 153.390 96.780 153.650 97.040 ;
        RECT 153.390 92.780 153.650 93.040 ;
        RECT 152.390 89.680 152.650 89.940 ;
        RECT 150.200 88.780 150.460 89.040 ;
        RECT 153.390 88.780 153.650 89.040 ;
        RECT -0.460 85.680 -0.200 85.940 ;
        RECT 150.200 84.780 150.460 85.040 ;
        RECT 152.390 84.780 152.650 85.040 ;
        RECT -0.460 81.680 -0.200 81.940 ;
        RECT 148.560 80.780 148.820 81.040 ;
        RECT 152.390 80.780 152.650 81.040 ;
        RECT 153.390 81.680 153.650 81.940 ;
        RECT -0.460 77.680 -0.200 77.940 ;
        RECT 153.390 77.680 153.650 77.940 ;
        RECT 156.390 85.680 156.650 85.940 ;
        RECT 150.200 76.780 150.460 77.040 ;
        RECT 152.390 76.780 152.650 77.040 ;
        RECT -0.460 73.680 -0.200 73.940 ;
        RECT 150.200 72.780 150.460 73.040 ;
        RECT -0.460 69.680 -0.200 69.940 ;
        RECT 155.390 73.680 155.650 73.940 ;
        RECT 152.390 69.680 152.650 69.940 ;
        RECT 148.560 68.780 148.820 69.040 ;
        RECT -0.460 65.680 -0.200 65.940 ;
        RECT 153.390 72.780 153.650 73.040 ;
        RECT 153.390 68.780 153.650 69.040 ;
        RECT 152.390 65.680 152.650 65.940 ;
        RECT 150.200 64.780 150.460 65.040 ;
        RECT 153.390 64.780 153.650 65.040 ;
        RECT -0.460 61.680 -0.200 61.940 ;
        RECT 150.200 60.780 150.460 61.040 ;
        RECT 152.390 60.780 152.650 61.040 ;
        RECT -0.460 57.680 -0.200 57.940 ;
        RECT 148.560 56.780 148.820 57.040 ;
        RECT 152.390 56.780 152.650 57.040 ;
        RECT 153.390 57.680 153.650 57.940 ;
        RECT -0.460 53.680 -0.200 53.940 ;
        RECT 153.390 53.680 153.650 53.940 ;
        RECT 154.390 61.680 154.650 61.940 ;
        RECT 150.200 52.780 150.460 53.040 ;
        RECT 152.390 52.780 152.650 53.040 ;
        RECT -0.460 49.680 -0.200 49.940 ;
        RECT 150.200 48.780 150.460 49.040 ;
        RECT -0.460 45.680 -0.200 45.940 ;
        RECT 152.390 45.680 152.650 45.940 ;
        RECT 148.560 44.780 148.820 45.040 ;
        RECT -0.460 41.680 -0.200 41.940 ;
        RECT 152.390 41.680 152.650 41.940 ;
        RECT 153.390 49.680 153.650 49.940 ;
        RECT 150.200 40.780 150.460 41.040 ;
        RECT -0.460 37.680 -0.200 37.940 ;
        RECT 161.390 48.780 161.650 49.040 ;
        RECT 161.390 44.780 161.650 45.040 ;
        RECT 161.390 40.780 161.650 41.040 ;
        RECT 161.390 37.680 161.650 37.940 ;
        RECT 160.390 29.340 160.650 29.600 ;
        RECT 189.190 29.340 189.450 29.600 ;
        RECT 159.390 25.280 159.650 25.540 ;
        RECT 189.190 25.280 189.450 25.540 ;
        RECT 158.390 21.500 158.650 21.760 ;
        RECT 189.190 21.500 189.450 21.760 ;
        RECT 157.390 17.440 157.650 17.700 ;
        RECT 189.190 17.440 189.450 17.700 ;
        RECT 156.390 13.660 156.650 13.920 ;
        RECT 189.190 13.660 189.450 13.920 ;
        RECT 155.390 9.600 155.650 9.860 ;
        RECT 189.190 9.600 189.450 9.860 ;
        RECT 154.390 5.820 154.650 6.080 ;
        RECT 189.190 5.820 189.450 6.080 ;
        RECT 153.390 1.760 153.650 2.020 ;
        RECT 189.190 1.760 189.450 2.020 ;
      LAYER Metal2 ;
        RECT -0.530 133.610 160.720 134.010 ;
        RECT 150.130 132.710 152.720 133.110 ;
        RECT 148.490 128.710 152.720 129.110 ;
        RECT 150.130 124.710 152.720 125.110 ;
        RECT -0.530 121.610 159.720 122.010 ;
        RECT 150.130 120.710 153.720 121.110 ;
        RECT -0.530 117.610 152.720 118.010 ;
        RECT 148.490 116.710 153.720 117.110 ;
        RECT -0.530 113.610 152.720 114.010 ;
        RECT 150.130 112.710 153.720 113.110 ;
        RECT -0.530 109.610 158.720 110.010 ;
        RECT 150.130 108.710 152.720 109.110 ;
        RECT -0.530 105.610 153.720 106.010 ;
        RECT 148.490 104.710 152.720 105.110 ;
        RECT -0.530 101.610 153.720 102.010 ;
        RECT 150.130 100.710 152.720 101.110 ;
        RECT -0.530 97.610 157.720 98.010 ;
        RECT 150.130 96.710 153.720 97.110 ;
        RECT -0.530 93.610 152.720 94.010 ;
        RECT 148.490 92.710 153.720 93.110 ;
        RECT -0.530 89.610 152.720 90.010 ;
        RECT 150.130 88.710 153.720 89.110 ;
        RECT -0.530 85.610 156.720 86.010 ;
        RECT 150.130 84.710 152.720 85.110 ;
        RECT -0.530 81.610 153.720 82.010 ;
        RECT 148.490 80.710 152.720 81.110 ;
        RECT -0.530 77.610 153.720 78.010 ;
        RECT 150.130 76.710 152.720 77.110 ;
        RECT -0.530 73.610 155.720 74.010 ;
        RECT 150.130 72.710 153.720 73.110 ;
        RECT -0.530 69.610 152.720 70.010 ;
        RECT 148.490 68.710 153.720 69.110 ;
        RECT -0.530 65.610 152.720 66.010 ;
        RECT 150.130 64.710 153.720 65.110 ;
        RECT -0.530 61.610 154.720 62.010 ;
        RECT 150.130 60.710 152.720 61.110 ;
        RECT -0.530 57.610 153.720 58.010 ;
        RECT 148.490 56.710 152.720 57.110 ;
        RECT -0.530 53.610 153.720 54.010 ;
        RECT 150.130 52.710 152.720 53.110 ;
        RECT -0.530 49.610 153.720 50.010 ;
        RECT 150.130 48.710 161.720 49.110 ;
        RECT -0.530 45.610 152.720 46.010 ;
        RECT 148.490 44.710 161.720 45.110 ;
        RECT -0.530 41.610 152.720 42.010 ;
        RECT 150.130 40.710 161.720 41.110 ;
        RECT -0.530 37.610 161.720 38.010 ;
        RECT 160.320 29.270 189.520 29.670 ;
        RECT 159.320 25.210 189.520 25.610 ;
        RECT 158.320 21.430 189.520 21.830 ;
        RECT 157.320 17.370 189.520 17.770 ;
        RECT 156.320 13.590 189.520 13.990 ;
        RECT 155.320 9.530 189.520 9.930 ;
        RECT 154.320 5.750 189.520 6.150 ;
        RECT 153.320 1.690 189.520 2.090 ;
  END
END r2r_dac_analog
END LIBRARY

